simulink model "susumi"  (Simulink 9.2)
settings: Solver=ode4  StartTime=0.0  StopTime=2  FixedStep=0.01  RelTol=1e-3
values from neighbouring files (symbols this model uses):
  alpha1 = (1-sin(phimax_rad))/(1+sin(phimax_rad))    [file9_2.m]    (also in file9_3.m = 1; file9_4.m = 1; file9_5.m = 1)
  K1 = 1    [file9_3.m]    (also in file9_5.m)
  K_nom = 10    [file9_1.m]    (also in file9_3.m; file9_5.m)
  T1 = 1/(sqrt(alpha1)*omega_max)    [file9_4.m]    (also in file9_5.m = 1)
  T_nom = 0.0933    [file9_1.m]    (also in file9_3.m; file9_5.m)
libraries: simulink x1

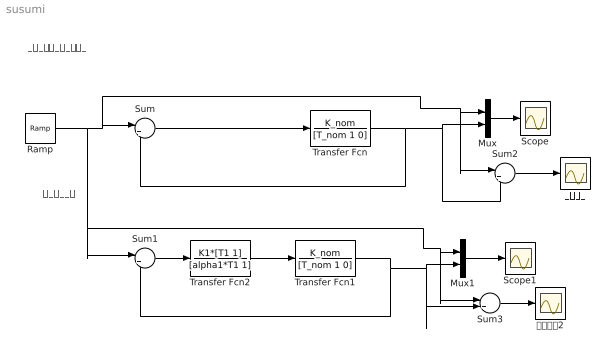
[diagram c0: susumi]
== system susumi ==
  note: コントローラがない場合
  note: 位相進み補償
  Mux : Mux  Inputs=2
  Mux1 : Mux  Inputs=2
  Ramp : simulink/Sources/Ramp  slope=1  start=0  InitialOutput=0
  Scope : Scope
  Scope1 : Scope
  Sum{,1..3} (4 alike) : Sum  Inputs=|+-
  Transfer Fcn : TransferFcn  Numerator=K_nom  Denominator=[T_nom 1 0]
  Transfer Fcn1 : TransferFcn  Numerator=K_nom  Denominator=[T_nom 1 0]
  Transfer Fcn2 : TransferFcn  Numerator=K1*[T1 1]  Denominator=[alpha1*T1 1]
  速度偏差 : Scope
  速度偏差2 : Scope
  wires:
  Sum/1 -> Transfer Fcn/1
  Ramp/1 -> Sum3/1, Mux1/1, Sum1/1, Sum2/1, Mux/1, Sum/1
  Transfer Fcn/1 -> Sum2/2, Mux/2, Sum/2
  Sum1/1 -> Transfer Fcn2/1
  Transfer Fcn1/1 -> Sum3/2, Mux1/2, Sum1/2
  Transfer Fcn2/1 -> Transfer Fcn1/1
  Mux/1 -> Scope/1
  Mux1/1 -> Scope1/1
  Sum2/1 -> 速度偏差/1
  Sum3/1 -> 速度偏差2/1
